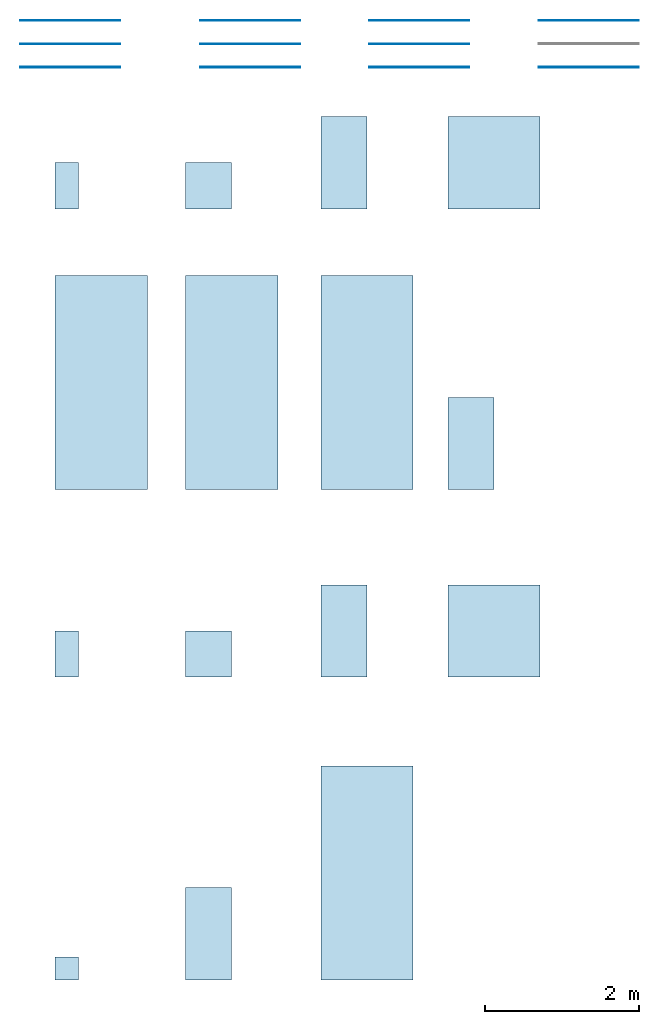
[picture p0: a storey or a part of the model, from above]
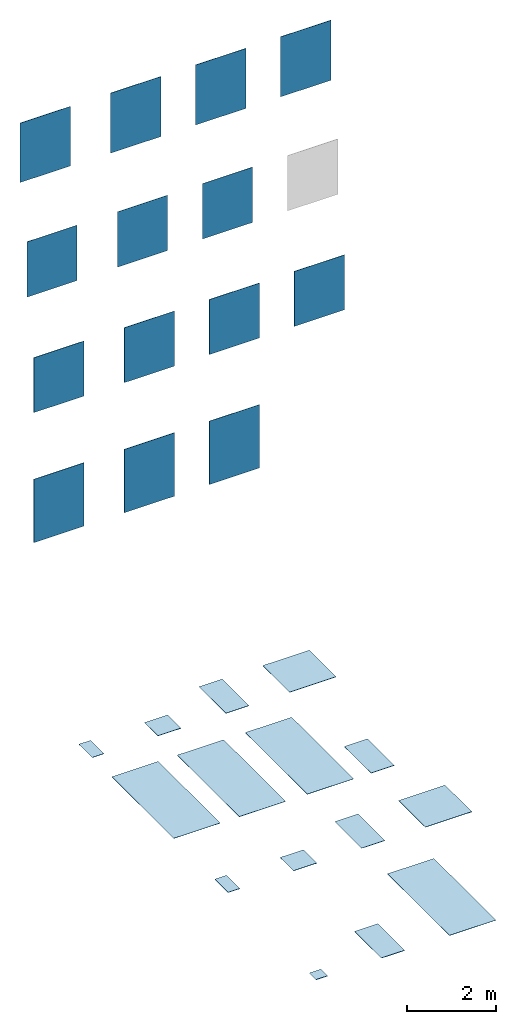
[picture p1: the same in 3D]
Properties of the parts of a building model (IFC2X3)

# File
Description: ViewDefinition [CoordinationView_V2.0], RevitIdentifiers [VersionGUID: 7166f2e5-5466-4735-995f-0db0073978aa, NumberOfSaves: 317], CoordinateReference [CoordinateBase: Shared Coordinates, ProjectSite: Internal]
File name: Project Number
Time: 2024-01-23T16:55:25+01:00
Written by: ODA SDAI 24.3
Made in: Autodesk Revit 24.1.11.26 (ENU) - IFC 24.1.11.26

# IfcProject, Project Number
LongName: Refin-Blended; Phase: Project Status

# IfcSite, Default
RefLatitude: 51, 30, 0, 549316; RefLongitude: 0, -7, -34, -450321; RefElevation: 0 mm

# IfcBuilding
Pset_BuildingCommon - NumberOfStoreys: 1

# IfcBuildingStorey: Level:Circle Head - Project Datum (2)
Pset_AirSideSystemInformation - sets with these values: 2
Name | LongName = Name | Elevation (mm)
Level 0 | Level 0 | 0
Level 1 | Level 1 | 4000

# IfcSlab: Floor:Floor_Tiles_Refin-Prestigio-Calacatta-Oro-120x278 RA40, Floor:Floor_Tiles_Refin-Prestigio-Calacatta-Oro-120x278 RA40:358765
In: Level 0
Type - PredefinedType: FLOOR; Material: Prestigio-Calacatta-Oro-120x278 RA40 6 mm, <Unnamed> 1 mm
Type - Pset_ConcreteElementGeneral - FireRating: INERT
Type - Pset_ElementShading - Color: WHITE
Type - Pset_FireRatingProperties - SurfaceSpreadOfFlame: INERT
Type - Pset_ManufacturerOccurrence - BarCode: N/A; SerialNumber: N/A
Type - Pset_ManufacturerTypeInformation - ArticleNumber: RA40; ModelReference: RA40; ModelLabel: CALACATTA ORO R 120X278; Manufacturer: info@refin.it; ProductionYear: N/A
Type - Pset_PrecastConcreteElementGeneral - SerialNumber: N/A
Type - Pset_ProductRequirements - Name: Prestigio_Calacatta_Oro_120X278 R; Category: Pr_35_93_96_19:Ceramic tiles
Type - Pset_QuantityTakeOff - Reference: N/A
Type - Pset_ReinforcementBarPitchOfSlab - Description: PORCELAIN STONEWARE TILE; Reference: N/A
Type - Pset_SlabCommon - Reference: N/A; IsExternal: no; AcousticRating: N/A; FireRating: INERT; SurfaceSpreadOfFlame: INERT
Type - Pset_Warranty - WarrantyContent: N/A; Exclusions: N/A
Pset_QuantityTakeOff - sets with these values: 2
Pset_SlabCommon - LoadBearing: no; PitchAngle: 0 deg

# IfcSlab: Floor:Floor_Tiles_Refin-Prestigio-Calacatta-Oro-Lucido-120x120 OY47, Floor:Floor_Tiles_Refin-Prestigio-Calacatta-Oro-Lucido-120x120 OY47:346245
In: Level 0
Type - PredefinedType: FLOOR; Material: Prestigio-Calacatta-Oro-Lucido-120x120 OY47 9 mm, <Unnamed> 1 mm
Type - Pset_ConcreteElementGeneral - FireRating: INERT
Type - Pset_ElementShading - Color: WHITE
Type - Pset_FireRatingProperties - SurfaceSpreadOfFlame: INERT
Type - Pset_ManufacturerOccurrence - BarCode: N/A; SerialNumber: N/A
Type - Pset_ManufacturerTypeInformation - ArticleNumber: OY47; ModelReference: OY47; ModelLabel: CALACATTA ORO LUCIDO R 120X120; Manufacturer: info@refin.it; ProductionYear: N/A
Type - Pset_PrecastConcreteElementGeneral - SerialNumber: N/A
Type - Pset_ProductRequirements - Name: Prestigio_Calacatta_Oro_Lucido_120X120 R; Category: Pr_35_93_96_19:Ceramic tiles
Type - Pset_QuantityTakeOff - Reference: N/A
Type - Pset_ReinforcementBarPitchOfSlab - Description: PORCELAIN STONEWARE TILE; Reference: N/A
Type - Pset_SlabCommon - Reference: N/A; IsExternal: no; AcousticRating: N/A; FireRating: INERT; SurfaceSpreadOfFlame: INERT
Type - Pset_Warranty - WarrantyContent: N/A; Exclusions: N/A
Pset_QuantityTakeOff - sets with these values: 2
Pset_SlabCommon - LoadBearing: no; PitchAngle: 0 deg

# IfcSlab: Floor:Floor_Tiles_Refin-Prestigio-Calacatta-Oro-Lucido-120x278 RA36, Floor:Floor_Tiles_Refin-Prestigio-Calacatta-Oro-Lucido-120x278 RA36:356121
In: Level 0
Type - PredefinedType: FLOOR; Material: Prestigio-Calacatta-Oro-Lucido-120x278 RA36 6 mm, <Unnamed> 1 mm
Type - Pset_ConcreteElementGeneral - FireRating: INERT
Type - Pset_ElementShading - Color: WHITE
Type - Pset_FireRatingProperties - SurfaceSpreadOfFlame: INERT
Type - Pset_ManufacturerOccurrence - BarCode: N/A; SerialNumber: N/A
Type - Pset_ManufacturerTypeInformation - ArticleNumber: RA36; ModelReference: RA36; ModelLabel: CALACATTA ORO LUCIDO R 120X278; Manufacturer: info@refin.it; ProductionYear: N/A
Type - Pset_PrecastConcreteElementGeneral - SerialNumber: N/A
Type - Pset_ProductRequirements - Name: Prestigio_Calacatta_Oro_Lucido_120X278 R; Category: Pr_35_93_96_19:Ceramic tiles
Type - Pset_QuantityTakeOff - Reference: N/A
Type - Pset_ReinforcementBarPitchOfSlab - Description: PORCELAIN STONEWARE TILE; Reference: N/A
Type - Pset_SlabCommon - Reference: N/A; IsExternal: no; AcousticRating: N/A; FireRating: INERT; SurfaceSpreadOfFlame: INERT
Type - Pset_Warranty - WarrantyContent: N/A; Exclusions: N/A
Pset_QuantityTakeOff - sets with these values: 2
Pset_SlabCommon - LoadBearing: no; PitchAngle: 0 deg

# IfcSlab: Floor:Floor_Tiles_Refin-Prestigio-Calacatta-Oro-Lucido-30x60 RC57, Floor:Floor_Tiles_Refin-Prestigio-Calacatta-Oro-Lucido-30x60 RC57:304668
In: Level 0
Type - PredefinedType: FLOOR; Material: Prestigio-Calacatta-Oro-Lucido-30x60 RC57 9 mm, <Unnamed> 1 mm
Type - Pset_ConcreteElementGeneral - FireRating: INERT
Type - Pset_ElementShading - Color: WHITE
Type - Pset_FireRatingProperties - SurfaceSpreadOfFlame: INERT
Type - Pset_ManufacturerOccurrence - BarCode: N/A; SerialNumber: N/A
Type - Pset_ManufacturerTypeInformation - ArticleNumber: RC57; ModelReference: RC57; ModelLabel: CALACATTA ORO LUCIDO R 30X60; Manufacturer: info@refin.it; ProductionYear: N/A
Type - Pset_PrecastConcreteElementGeneral - SerialNumber: N/A
Type - Pset_ProductRequirements - Name: Prestigio_Calacatta_Oro_Lucido_30X60 R; Category: Pr_35_93_96_19:Ceramic tiles
Type - Pset_QuantityTakeOff - Reference: N/A
Type - Pset_ReinforcementBarPitchOfSlab - Description: PORCELAIN STONEWARE TILE; Reference: N/A
Type - Pset_SlabCommon - Reference: N/A; IsExternal: no; AcousticRating: N/A; FireRating: INERT; SurfaceSpreadOfFlame: INERT
Type - Pset_Warranty - WarrantyContent: N/A; Exclusions: N/A
Pset_QuantityTakeOff - sets with these values: 2
Pset_SlabCommon - LoadBearing: no; PitchAngle: 0 deg

# IfcSlab: Floor:Floor_Tiles_Refin-Prestigio-Calacatta-Oro-Lucido-60x120 RC42, Floor:Floor_Tiles_Refin-Prestigio-Calacatta-Oro-Lucido-60x120 RC42:285295
In: Level 0
Type - PredefinedType: FLOOR; Material: Prestigio-Calacatta-Oro-Lucido-60x120 RC42 9 mm, <Unnamed> 1 mm
Type - Pset_ConcreteElementGeneral - FireRating: INERT
Type - Pset_ElementShading - Color: WHITE
Type - Pset_FireRatingProperties - SurfaceSpreadOfFlame: INERT
Type - Pset_ManufacturerOccurrence - BarCode: N/A; SerialNumber: N/A
Type - Pset_ManufacturerTypeInformation - ArticleNumber: RC42; ModelReference: RC42; ModelLabel: CALACATTA ORO LUCIDO R 60X120; Manufacturer: info@refin.it; ProductionYear: N/A
Type - Pset_PrecastConcreteElementGeneral - SerialNumber: N/A
Type - Pset_ProductRequirements - Name: Prestigio_Calacatta_Oro_Lucido_60X120 R; Category: Pr_35_93_96_19:Ceramic tiles
Type - Pset_QuantityTakeOff - Reference: N/A
Type - Pset_ReinforcementBarPitchOfSlab - Description: PORCELAIN STONEWARE TILE; Reference: N/A
Type - Pset_SlabCommon - Reference: N/A; IsExternal: no; AcousticRating: N/A; FireRating: INERT; SurfaceSpreadOfFlame: INERT
Type - Pset_Warranty - WarrantyContent: N/A; Exclusions: N/A
Pset_QuantityTakeOff - sets with these values: 2
Pset_SlabCommon - LoadBearing: no; PitchAngle: 0 deg

# IfcSlab: Floor:Floor_Tiles_Refin-Prestigio-Calacatta-Oro-Lucido-60x60 RA49, Floor:Floor_Tiles_Refin-Prestigio-Calacatta-Oro-Lucido-60x60 RA49:324498
In: Level 0
Type - PredefinedType: FLOOR; Material: Prestigio-Calacatta-Oro-Lucido-60x60 RA49 9 mm, <Unnamed> 1 mm
Type - Pset_ConcreteElementGeneral - FireRating: INERT
Type - Pset_ElementShading - Color: WHITE
Type - Pset_FireRatingProperties - SurfaceSpreadOfFlame: INERT
Type - Pset_ManufacturerOccurrence - BarCode: N/A; SerialNumber: N/A
Type - Pset_ManufacturerTypeInformation - ArticleNumber: RA49; ModelReference: RA49; ModelLabel: CALACATTA ORO LUCIDO R 60X60; Manufacturer: info@refin.it; ProductionYear: N/A
Type - Pset_PrecastConcreteElementGeneral - SerialNumber: N/A
Type - Pset_ProductRequirements - Name: Prestigio_Calacatta_Oro_Lucido_60X60 R; Category: Pr_35_93_96_19:Ceramic tiles
Type - Pset_QuantityTakeOff - Reference: N/A
Type - Pset_ReinforcementBarPitchOfSlab - Description: PORCELAIN STONEWARE TILE; Reference: N/A
Type - Pset_SlabCommon - Reference: N/A; IsExternal: no; AcousticRating: N/A; FireRating: INERT; SurfaceSpreadOfFlame: INERT
Type - Pset_Warranty - WarrantyContent: N/A; Exclusions: N/A
Pset_QuantityTakeOff - sets with these values: 2
Pset_SlabCommon - LoadBearing: no; PitchAngle: 0 deg

# IfcSlab: Floor:Floor_Tiles_Refin-Prestigio-Calacatta-Oro-Lucido-Craquele-120x278 RB39, Floor:Floor_Tiles_Refin-Prestigio-Calacatta-Oro-Lucido-Craquele-120x278 RB39:356309
In: Level 0
Type - PredefinedType: FLOOR; Material: Prestigio-Calacatta-Oro-Lucido-Craquele-120x278 RB39 6 mm, <Unnamed> 1 mm
Type - Pset_ConcreteElementGeneral - FireRating: INERT
Type - Pset_ElementShading - Color: WHITE
Type - Pset_FireRatingProperties - SurfaceSpreadOfFlame: INERT
Type - Pset_ManufacturerOccurrence - BarCode: N/A; SerialNumber: N/A
Type - Pset_ManufacturerTypeInformation - ArticleNumber: RB39; ModelReference: RB39; ModelLabel: CALACATTA ORO LUCIDO CRAQUELE R 120X278; Manufacturer: info@refin.it; ProductionYear: N/A
Type - Pset_PrecastConcreteElementGeneral - SerialNumber: N/A
Type - Pset_ProductRequirements - Name: Prestigio_Calacatta_Oro_Lucido_Craquele_120X278 R; Category: Pr_35_93_96_19:Ceramic tiles
Type - Pset_QuantityTakeOff - Reference: N/A
Type - Pset_ReinforcementBarPitchOfSlab - Description: PORCELAIN STONEWARE TILE; Reference: N/A
Type - Pset_SlabCommon - Reference: N/A; IsExternal: no; AcousticRating: N/A; FireRating: INERT; SurfaceSpreadOfFlame: INERT
Type - Pset_Warranty - WarrantyContent: N/A; Exclusions: N/A
Pset_QuantityTakeOff - sets with these values: 2
Pset_SlabCommon - LoadBearing: no; PitchAngle: 0 deg

# IfcSlab: Floor:Floor_Tiles_Refin-Prestigio-Calacatta-Oro-Lucido-Mesh-120x278 RB41, Floor:Floor_Tiles_Refin-Prestigio-Calacatta-Oro-Lucido-Mesh-120x278 RB41:356759
In: Level 0
Type - PredefinedType: FLOOR; Material: Prestigio-Calacatta-Oro-Lucido-Mesh-120x278 RB41 6 mm, <Unnamed> 1 mm
Type - Pset_ConcreteElementGeneral - FireRating: INERT
Type - Pset_ElementShading - Color: WHITE
Type - Pset_FireRatingProperties - SurfaceSpreadOfFlame: INERT
Type - Pset_ManufacturerOccurrence - BarCode: N/A; SerialNumber: N/A
Type - Pset_ManufacturerTypeInformation - ArticleNumber: RB41; ModelReference: RB41; ModelLabel: CALACATTA ORO LUCIDO MESH R 120X278; Manufacturer: info@refin.it; ProductionYear: N/A
Type - Pset_PrecastConcreteElementGeneral - SerialNumber: N/A
Type - Pset_ProductRequirements - Name: Prestigio_Calacatta_Oro_Lucido_Mesh_120X278 R; Category: Pr_35_93_96_19:Ceramic tiles
Type - Pset_QuantityTakeOff - Reference: N/A
Type - Pset_ReinforcementBarPitchOfSlab - Description: PORCELAIN STONEWARE TILE; Reference: N/A
Type - Pset_SlabCommon - Reference: N/A; IsExternal: no; AcousticRating: N/A; FireRating: INERT; SurfaceSpreadOfFlame: INERT
Type - Pset_Warranty - WarrantyContent: N/A; Exclusions: N/A
Pset_QuantityTakeOff - sets with these values: 2
Pset_SlabCommon - LoadBearing: no; PitchAngle: 0 deg

# IfcSlab: Floor:Floor_Tiles_Refin-Prestigio-Calacatta-Oro-Matt-60x120 RC52, Floor:Floor_Tiles_Refin-Prestigio-Calacatta-Oro-Matt-60x120 RC52:356962
In: Level 0
Type - PredefinedType: FLOOR; Material: Prestigio-Calacatta-Oro-Matt-60x120 RC52 9 mm, <Unnamed> 1 mm
Type - Pset_ConcreteElementGeneral - FireRating: INERT
Type - Pset_ElementShading - Color: WHITE
Type - Pset_FireRatingProperties - SurfaceSpreadOfFlame: INERT
Type - Pset_ManufacturerOccurrence - BarCode: N/A; SerialNumber: N/A
Type - Pset_ManufacturerTypeInformation - ArticleNumber: RC52; ModelReference: RC52; ModelLabel: CALACATTA ORO MATT R 60X120; Manufacturer: info@refin.it; ProductionYear: N/A
Type - Pset_PrecastConcreteElementGeneral - SerialNumber: N/A
Type - Pset_ProductRequirements - Name: Prestigio_Calacatta_Oro_Matt_60X120 R; Category: Pr_35_93_96_19:Ceramic tiles
Type - Pset_QuantityTakeOff - Reference: N/A
Type - Pset_ReinforcementBarPitchOfSlab - Description: PORCELAIN STONEWARE TILE; Reference: N/A
Type - Pset_SlabCommon - Reference: N/A; IsExternal: no; AcousticRating: N/A; FireRating: INERT; SurfaceSpreadOfFlame: INERT
Type - Pset_Warranty - WarrantyContent: N/A; Exclusions: N/A
Pset_QuantityTakeOff - sets with these values: 2
Pset_SlabCommon - LoadBearing: no; PitchAngle: 0 deg

# IfcSlab: Floor:Floor_Tiles_Refin-Prestigio-Calacatta-Oro-Mosaico-30x30 RB56, Floor:Floor_Tiles_Refin-Prestigio-Calacatta-Oro-Mosaico-30x30 RB56:358331
In: Level 0
Type - PredefinedType: FLOOR; Material: Prestigio-Calacatta-Oro-Mosaico-30x30 RB56 9 mm, <Unnamed> 1 mm
Type - Pset_ConcreteElementGeneral - FireRating: INERT
Type - Pset_ElementShading - Color: WHITE
Type - Pset_FireRatingProperties - SurfaceSpreadOfFlame: INERT
Type - Pset_ManufacturerOccurrence - BarCode: N/A; SerialNumber: N/A
Type - Pset_ManufacturerTypeInformation - ArticleNumber: RB56; ModelReference: RB56; ModelLabel: CALACATTA ORO MOSAICO R 30X30; Manufacturer: info@refin.it; ProductionYear: N/A
Type - Pset_PrecastConcreteElementGeneral - SerialNumber: N/A
Type - Pset_ProductRequirements - Name: Prestigio_Calacatta_Oro_Mosaico_30X30 R; Category: Pr_35_93_96_19:Ceramic tiles
Type - Pset_QuantityTakeOff - Reference: N/A
Type - Pset_ReinforcementBarPitchOfSlab - Description: PORCELAIN STONEWARE TILE; Reference: N/A
Type - Pset_SlabCommon - Reference: N/A; IsExternal: no; AcousticRating: N/A; FireRating: INERT; SurfaceSpreadOfFlame: INERT
Type - Pset_Warranty - WarrantyContent: N/A; Exclusions: N/A
Pset_QuantityTakeOff - sets with these values: 2
Pset_SlabCommon - LoadBearing: no; PitchAngle: 0 deg

# IfcSlab: Floor:Floor_Tiles_Refin-Prestigio-Calacatta-Oro-Onde-60x120 RB12, Floor:Floor_Tiles_Refin-Prestigio-Calacatta-Oro-Onde-60x120 RB12:353888
In: Level 0
Type - PredefinedType: FLOOR; Material: Prestigio-Calacatta-Oro-Onde-60x120 RB12 9 mm, <Unnamed> 1 mm
Type - Pset_ConcreteElementGeneral - FireRating: INERT
Type - Pset_ElementShading - Color: WHITE
Type - Pset_FireRatingProperties - SurfaceSpreadOfFlame: INERT
Type - Pset_ManufacturerOccurrence - BarCode: N/A; SerialNumber: N/A
Type - Pset_ManufacturerTypeInformation - ArticleNumber: RB12; ModelReference: RB12; ModelLabel: CALACATTA ORO ONDE R 60X120; Manufacturer: info@refin.it; ProductionYear: N/A
Type - Pset_PrecastConcreteElementGeneral - SerialNumber: N/A
Type - Pset_ProductRequirements - Name: Prestigio_Calacatta_Oro_Onde_60X120 R; Category: Pr_35_93_96_19:Ceramic tiles
Type - Pset_QuantityTakeOff - Reference: N/A
Type - Pset_ReinforcementBarPitchOfSlab - Description: PORCELAIN STONEWARE TILE; Reference: N/A
Type - Pset_SlabCommon - Reference: N/A; IsExternal: no; AcousticRating: N/A; FireRating: INERT; SurfaceSpreadOfFlame: INERT
Type - Pset_Warranty - WarrantyContent: N/A; Exclusions: N/A
Pset_QuantityTakeOff - sets with these values: 2
Pset_SlabCommon - LoadBearing: no; PitchAngle: 0 deg

# IfcSlab: Floor:Floor_Tiles_Refin-Prestigio-Calacatta-Oro-Soft-120x120 OY58, Floor:Floor_Tiles_Refin-Prestigio-Calacatta-Oro-Soft-120x120 OY58:357396
In: Level 0
Type - PredefinedType: FLOOR; Material: Prestigio-Calacatta-Oro-Soft-120x120 OY58 9 mm, <Unnamed> 1 mm
Type - Pset_ConcreteElementGeneral - FireRating: INERT
Type - Pset_ElementShading - Color: WHITE
Type - Pset_FireRatingProperties - SurfaceSpreadOfFlame: INERT
Type - Pset_ManufacturerOccurrence - BarCode: N/A; SerialNumber: N/A
Type - Pset_ManufacturerTypeInformation - ArticleNumber: OY58; ModelReference: OY58; ModelLabel: CALACATTA ORO SOFT R 120X120; Manufacturer: info@refin.it; ProductionYear: N/A
Type - Pset_PrecastConcreteElementGeneral - SerialNumber: N/A
Type - Pset_ProductRequirements - Name: Prestigio_Calacatta_Oro_Soft_120X120 R; Category: Pr_35_93_96_19:Ceramic tiles
Type - Pset_QuantityTakeOff - Reference: N/A
Type - Pset_ReinforcementBarPitchOfSlab - Description: PORCELAIN STONEWARE TILE; Reference: N/A
Type - Pset_SlabCommon - Reference: N/A; IsExternal: no; AcousticRating: N/A; FireRating: INERT; SurfaceSpreadOfFlame: INERT
Type - Pset_Warranty - WarrantyContent: N/A; Exclusions: N/A
Pset_QuantityTakeOff - sets with these values: 2
Pset_SlabCommon - LoadBearing: no; PitchAngle: 0 deg

# IfcSlab: Floor:Floor_Tiles_Refin-Prestigio-Calacatta-Oro-Soft-30x60 RC62, Floor:Floor_Tiles_Refin-Prestigio-Calacatta-Oro-Soft-30x60 RC62:357145
In: Level 0
Type - PredefinedType: FLOOR; Material: Prestigio-Calacatta-Oro-Soft-30x60 RC62 9 mm, <Unnamed> 1 mm
Type - Pset_ConcreteElementGeneral - FireRating: INERT
Type - Pset_ElementShading - Color: WHITE
Type - Pset_FireRatingProperties - SurfaceSpreadOfFlame: INERT
Type - Pset_ManufacturerOccurrence - BarCode: N/A; SerialNumber: N/A
Type - Pset_ManufacturerTypeInformation - ArticleNumber: RC62; ModelReference: RC62; ModelLabel: CALACATTA ORO SOFT R 30X60; Manufacturer: info@refin.it; ProductionYear: N/A
Type - Pset_PrecastConcreteElementGeneral - SerialNumber: N/A
Type - Pset_ProductRequirements - Name: Prestigio_Calacatta_Oro_Soft_30X60 R; Category: Pr_35_93_96_19:Ceramic tiles
Type - Pset_QuantityTakeOff - Reference: N/A
Type - Pset_ReinforcementBarPitchOfSlab - Description: PORCELAIN STONEWARE TILE; Reference: N/A
Type - Pset_SlabCommon - Reference: N/A; IsExternal: no; AcousticRating: N/A; FireRating: INERT; SurfaceSpreadOfFlame: INERT
Type - Pset_Warranty - WarrantyContent: N/A; Exclusions: N/A
Pset_QuantityTakeOff - sets with these values: 2
Pset_SlabCommon - LoadBearing: no; PitchAngle: 0 deg

# IfcSlab: Floor:Floor_Tiles_Refin-Prestigio-Calacatta-Oro-Soft-60x120 RC47, Floor:Floor_Tiles_Refin-Prestigio-Calacatta-Oro-Soft-60x120 RC47:357388
In: Level 0
Type - PredefinedType: FLOOR; Material: Prestigio-Calacatta-Oro-Soft-60x120 RC47 6 mm, <Unnamed> 1 mm
Type - Pset_ConcreteElementGeneral - FireRating: INERT
Type - Pset_ElementShading - Color: WHITE
Type - Pset_FireRatingProperties - SurfaceSpreadOfFlame: INERT
Type - Pset_ManufacturerOccurrence - BarCode: N/A; SerialNumber: N/A
Type - Pset_ManufacturerTypeInformation - ArticleNumber: RC47; ModelReference: RC47; ModelLabel: CALACATTA ORO SOFT R 60X120; Manufacturer: info@refin.it; ProductionYear: N/A
Type - Pset_PrecastConcreteElementGeneral - SerialNumber: N/A
Type - Pset_ProductRequirements - Name: Prestigio_Calacatta_Oro_Soft_60X120 R; Category: Pr_35_93_96_19:Ceramic tiles
Type - Pset_QuantityTakeOff - Reference: N/A
Type - Pset_ReinforcementBarPitchOfSlab - Description: PORCELAIN STONEWARE TILE; Reference: N/A
Type - Pset_SlabCommon - Reference: N/A; IsExternal: no; AcousticRating: N/A; FireRating: INERT; SurfaceSpreadOfFlame: INERT
Type - Pset_Warranty - WarrantyContent: N/A; Exclusions: N/A
Pset_QuantityTakeOff - sets with these values: 2
Pset_SlabCommon - LoadBearing: no; PitchAngle: 0 deg

# IfcSlab: Floor:Floor_Tiles_Refin-Prestigio-Calacatta-Oro-Soft-60x60 RB85, Floor:Floor_Tiles_Refin-Prestigio-Calacatta-Oro-Soft-60x60 RB85:357443
In: Level 0
Type - PredefinedType: FLOOR; Material: Prestigio-Calacatta-Oro-Lucido-60x60 RA49 9 mm, <Unnamed> 1 mm
Type - Pset_ConcreteElementGeneral - FireRating: INERT
Type - Pset_ElementShading - Color: WHITE
Type - Pset_FireRatingProperties - SurfaceSpreadOfFlame: INERT
Type - Pset_ManufacturerOccurrence - BarCode: N/A; SerialNumber: N/A
Type - Pset_ManufacturerTypeInformation - ArticleNumber: RB85; ModelReference: RB85; ModelLabel: CALACATTA ORO SOFT R 60X60; Manufacturer: info@refin.it; ProductionYear: N/A
Type - Pset_PrecastConcreteElementGeneral - SerialNumber: N/A
Type - Pset_ProductRequirements - Name: Prestigio_Calacatta_Oro_Soft_60X60 R; Category: Pr_35_93_96_19:Ceramic tiles
Type - Pset_QuantityTakeOff - Reference: N/A
Type - Pset_ReinforcementBarPitchOfSlab - Description: PORCELAIN STONEWARE TILE; Reference: N/A
Type - Pset_SlabCommon - Reference: N/A; IsExternal: no; AcousticRating: N/A; FireRating: INERT; SurfaceSpreadOfFlame: INERT
Type - Pset_Warranty - WarrantyContent: N/A; Exclusions: N/A
Pset_QuantityTakeOff - sets with these values: 2
Pset_SlabCommon - LoadBearing: no; PitchAngle: 0 deg

# IfcWallStandardCase: Basic Wall:Wall_Tiles_Refin-Prestigio-Calacatta-Oro-Lucido-120x120 OY47, Basic Wall:Wall_Tiles_Refin-Prestigio-Calacatta-Oro-Lucido-120x120 OY47:346671
In: Level 0
Type - PredefinedType: STANDARD; Material: <Unnamed> 1 mm, Prestigio-Calacatta-Oro-Lucido-120x120 OY47 9 mm
Type - Pset_ElementShading - Color: WHITE
Type - Pset_FireRatingProperties - SurfaceSpreadOfFlame: INERT
Type - Pset_ManufacturerOccurrence - BarCode: N/A; SerialNumber: N/A
Type - Pset_ManufacturerTypeInformation - ArticleNumber: OY47; ModelReference: OY47; ModelLabel: CALACATTA ORO LUCIDO R 120X120; Manufacturer: info@refin.it; ProductionYear: N/A
Type - Pset_PrecastConcreteElementGeneral - SerialNumber: N/A
Type - Pset_ProductRequirements - Name: Prestigio_Calacatta_Oro_Lucido_120X120 R; Category: Pr_35_93_96_19:Ceramic tiles
Type - Pset_QuantityTakeOff - Reference: N/A
Type - Pset_ReinforcementBarPitchOfWall - Description: PORCELAIN STONEWARE TILE; Reference: N/A
Type - Pset_WallCommon - Reference: N/A; IsExternal: no; AcousticRating: N/A; SurfaceSpreadOfFlame: INERT
Type - Pset_Warranty - WarrantyContent: N/A; Exclusions: N/A
Pset_QuantityTakeOff - sets with these values: 2
Pset_WallCommon - LoadBearing: no; ExtendToStructure: no

# IfcWallStandardCase: Basic Wall:Wall_Tiles_Refin-Prestigio-Calacatta-Oro-Lucido-120x278 RA36, Basic Wall:Wall_Tiles_Refin-Prestigio-Calacatta-Oro-Lucido-120x278 RA36:335038
In: Level 0
Type - PredefinedType: STANDARD; Material: <Unnamed> 1 mm, Prestigio-Calacatta-Oro-Lucido-120x278 RA36 6 mm
Type - Pset_ElementShading - Color: WHITE
Type - Pset_FireRatingProperties - SurfaceSpreadOfFlame: INERT
Type - Pset_ManufacturerOccurrence - BarCode: N/A; SerialNumber: N/A
Type - Pset_ManufacturerTypeInformation - ArticleNumber: RB39; ModelReference: RB39; ModelLabel: CALACATTA ORO LUCIDO R 120X278; Manufacturer: info@refin.it; ProductionYear: N/A
Type - Pset_PrecastConcreteElementGeneral - SerialNumber: N/A
Type - Pset_ProductRequirements - Name: Prestigio_Calacatta_Oro_Lucido_120X278 R; Category: Pr_35_93_96_19:Ceramic tiles
Type - Pset_QuantityTakeOff - Reference: N/A
Type - Pset_ReinforcementBarPitchOfWall - Description: PORCELAIN STONEWARE TILE; Reference: N/A
Type - Pset_WallCommon - Reference: N/A; IsExternal: no; AcousticRating: N/A; SurfaceSpreadOfFlame: INERT
Type - Pset_Warranty - WarrantyContent: N/A; Exclusions: N/A
Pset_QuantityTakeOff - sets with these values: 2
Pset_WallCommon - LoadBearing: no; ExtendToStructure: no

# IfcWallStandardCase: Basic Wall:Wall_Tiles_Refin-Prestigio-Calacatta-Oro-Lucido-30x60 RC57, Basic Wall:Wall_Tiles_Refin-Prestigio-Calacatta-Oro-Lucido-30x60 RC57:334895
In: Level 0
Type - PredefinedType: STANDARD; Material: <Unnamed> 1 mm, Prestigio-Calacatta-Oro-Lucido-30x60 RC57 9 mm
Type - Pset_ElementShading - Color: WHITE
Type - Pset_FireRatingProperties - SurfaceSpreadOfFlame: INERT
Type - Pset_ManufacturerOccurrence - BarCode: N/A; SerialNumber: N/A
Type - Pset_ManufacturerTypeInformation - ArticleNumber: RC57; ModelReference: RC57; ModelLabel: CALACATTA ORO LUCIDO R 30X60; Manufacturer: info@refin.it; ProductionYear: N/A
Type - Pset_PrecastConcreteElementGeneral - SerialNumber: N/A
Type - Pset_ProductRequirements - Name: Prestigio_Calacatta_Oro_Lucido_30X60 R; Category: Pr_35_93_96_19:Ceramic tiles
Type - Pset_QuantityTakeOff - Reference: N/A
Type - Pset_ReinforcementBarPitchOfWall - Description: PORCELAIN STONEWARE TILE; Reference: N/A
Type - Pset_WallCommon - Reference: N/A; IsExternal: no; AcousticRating: N/A; SurfaceSpreadOfFlame: INERT
Type - Pset_Warranty - WarrantyContent: N/A; Exclusions: N/A
Pset_QuantityTakeOff - sets with these values: 2
Pset_WallCommon - LoadBearing: no; ExtendToStructure: no

# IfcWallStandardCase: Basic Wall:Wall_Tiles_Refin-Prestigio-Calacatta-Oro-Lucido-60x120 RC42, Basic Wall:Wall_Tiles_Refin-Prestigio-Calacatta-Oro-Lucido-60x120 RC42:334553
In: Level 0
Type - PredefinedType: STANDARD; Material: <Unnamed> 1 mm, Prestigio-Calacatta-Oro-Lucido-60x120 RC42 9 mm
Type - Pset_ElementShading - Color: WHITE
Type - Pset_FireRatingProperties - SurfaceSpreadOfFlame: INERT
Type - Pset_ManufacturerOccurrence - BarCode: N/A; SerialNumber: N/A
Type - Pset_ManufacturerTypeInformation - ArticleNumber: RC42; ModelReference: RC42; ModelLabel: CALACATTA ORO LUCIDO R 60X120; Manufacturer: info@refin.it; ProductionYear: N/A
Type - Pset_PrecastConcreteElementGeneral - SerialNumber: N/A
Type - Pset_ProductRequirements - Name: Prestigio_Calacatta_Oro_Lucido_60X120 R; Category: Pr_35_93_96_19:Ceramic tiles
Type - Pset_QuantityTakeOff - Reference: N/A
Type - Pset_ReinforcementBarPitchOfWall - Description: PORCELAIN STONEWARE TILE; Reference: N/A
Type - Pset_WallCommon - Reference: N/A; IsExternal: no; AcousticRating: N/A; SurfaceSpreadOfFlame: INERT
Type - Pset_Warranty - WarrantyContent: N/A; Exclusions: N/A
Pset_QuantityTakeOff - sets with these values: 2
Pset_WallCommon - LoadBearing: no; ExtendToStructure: no

# IfcWallStandardCase: Basic Wall:Wall_Tiles_Refin-Prestigio-Calacatta-Oro-Lucido-60x60 RA49, Basic Wall:Wall_Tiles_Refin-Prestigio-Calacatta-Oro-Lucido-60x60 RA49:333696
In: Level 0
Type - PredefinedType: STANDARD; Material: <Unnamed> 1 mm, Prestigio-Calacatta-Oro-Lucido-60x60 RA49 9 mm
Type - Pset_ElementShading - Color: WHITE
Type - Pset_FireRatingProperties - SurfaceSpreadOfFlame: INERT
Type - Pset_ManufacturerOccurrence - BarCode: N/A; SerialNumber: N/A
Type - Pset_ManufacturerTypeInformation - ArticleNumber: RA49; ModelReference: RA49; ModelLabel: CALACATTA ORO LUCIDO R 60X60; Manufacturer: info@refin.it; ProductionYear: N/A
Type - Pset_PrecastConcreteElementGeneral - SerialNumber: N/A
Type - Pset_ProductRequirements - Name: Prestigio_Calacatta_Oro_Lucido_60X60 R; Category: Pr_35_93_96_19:Ceramic tiles
Type - Pset_QuantityTakeOff - Reference: N/A
Type - Pset_ReinforcementBarPitchOfWall - Description: PORCELAIN STONEWARE TILE; Reference: N/A
Type - Pset_WallCommon - Reference: N/A; IsExternal: no; AcousticRating: N/A; SurfaceSpreadOfFlame: INERT
Type - Pset_Warranty - WarrantyContent: N/A; Exclusions: N/A
Pset_QuantityTakeOff - sets with these values: 2
Pset_WallCommon - LoadBearing: no; ExtendToStructure: no

# IfcWallStandardCase: Basic Wall:Wall_Tiles_Refin-Prestigio-Calacatta-Oro-Lucido-Craquele-120x278 RB39, Basic Wall:Wall_Tiles_Refin-Prestigio-Calacatta-Oro-Lucido-Craquele-120x278 RB39:335490
In: Level 0
Type - PredefinedType: STANDARD; Material: <Unnamed> 1 mm, Prestigio-Calacatta-Oro-Lucido-Craquele-120x278 RB39 6 mm
Type - Pset_ElementShading - Color: WHITE
Type - Pset_FireRatingProperties - SurfaceSpreadOfFlame: INERT
Type - Pset_ManufacturerOccurrence - BarCode: N/A; SerialNumber: N/A
Type - Pset_ManufacturerTypeInformation - ArticleNumber: RB39; ModelReference: RB39; ModelLabel: CALACATTA ORO LUCIDO CRAQUELE R 120X278; Manufacturer: info@refin.it; ProductionYear: N/A
Type - Pset_PrecastConcreteElementGeneral - SerialNumber: N/A
Type - Pset_ProductRequirements - Name: Prestigio_Calacatta_Oro_Lucido_Craquele_120X278 R; Category: Pr_35_93_96_19:Ceramic tiles
Type - Pset_QuantityTakeOff - Reference: N/A
Type - Pset_ReinforcementBarPitchOfWall - Description: PORCELAIN STONEWARE TILE; Reference: N/A
Type - Pset_WallCommon - Reference: N/A; IsExternal: no; AcousticRating: N/A; SurfaceSpreadOfFlame: INERT
Type - Pset_Warranty - WarrantyContent: N/A; Exclusions: N/A
Pset_QuantityTakeOff - sets with these values: 2
Pset_WallCommon - LoadBearing: no; ExtendToStructure: no

# IfcWallStandardCase: Basic Wall:Wall_Tiles_Refin-Prestigio-Calacatta-Oro-Lucido-Mesh-120x278 RB41, Basic Wall:Wall_Tiles_Refin-Prestigio-Calacatta-Oro-Lucido-Mesh-120x278 RB41:335882
In: Level 0
Type - PredefinedType: STANDARD; Material: <Unnamed> 1 mm, Prestigio-Calacatta-Oro-Lucido-Mesh-120x278 RB41 6 mm
Type - Pset_ElementShading - Color: WHITE
Type - Pset_FireRatingProperties - SurfaceSpreadOfFlame: INERT
Type - Pset_ManufacturerOccurrence - BarCode: N/A; SerialNumber: N/A
Type - Pset_ManufacturerTypeInformation - ArticleNumber: RB41; ModelReference: RB41; ModelLabel: CALACATTA ORO LUCIDO MESH R 120X278; Manufacturer: info@refin.it; ProductionYear: N/A
Type - Pset_PrecastConcreteElementGeneral - SerialNumber: N/A
Type - Pset_ProductRequirements - Name: Prestigio_Calacatta_Oro_Lucido_Mesh_120X278 R; Category: Pr_35_93_96_19:Ceramic tiles
Type - Pset_QuantityTakeOff - Reference: N/A
Type - Pset_ReinforcementBarPitchOfWall - Description: PORCELAIN STONEWARE TILE; Reference: N/A
Type - Pset_WallCommon - Reference: N/A; IsExternal: no; AcousticRating: N/A; SurfaceSpreadOfFlame: INERT
Type - Pset_Warranty - WarrantyContent: N/A; Exclusions: N/A
Pset_QuantityTakeOff - sets with these values: 2
Pset_WallCommon - LoadBearing: no; ExtendToStructure: no

# IfcWallStandardCase: Basic Wall:Wall_Tiles_Refin-Prestigio-Calacatta-Oro-Matt-60x120 RC52, Basic Wall:Wall_Tiles_Refin-Prestigio-Calacatta-Oro-Matt-60x120 RC52:346686
In: Level 0
Type - PredefinedType: STANDARD; Material: <Unnamed> 1 mm, Prestigio-Calacatta-Oro-Matt-60x120 RC52 9 mm
Type - Pset_ElementShading - Color: WHITE
Type - Pset_FireRatingProperties - SurfaceSpreadOfFlame: INERT
Type - Pset_ManufacturerOccurrence - BarCode: N/A; SerialNumber: N/A
Type - Pset_ManufacturerTypeInformation - ArticleNumber: RC52; ModelReference: RC52; ModelLabel: CALACATTA ORO MATT R 60X120; Manufacturer: info@refin.it; ProductionYear: N/A
Type - Pset_PrecastConcreteElementGeneral - SerialNumber: N/A
Type - Pset_ProductRequirements - Name: Prestigio_Calacatta_Oro_Matt_60X120 R; Category: Pr_35_93_96_19:Ceramic tiles
Type - Pset_QuantityTakeOff - Reference: N/A
Type - Pset_ReinforcementBarPitchOfWall - Description: PORCELAIN STONEWARE TILE; Reference: N/A
Type - Pset_WallCommon - Reference: N/A; IsExternal: no; AcousticRating: N/A; SurfaceSpreadOfFlame: INERT
Type - Pset_Warranty - WarrantyContent: N/A; Exclusions: N/A
Pset_QuantityTakeOff - sets with these values: 2
Pset_WallCommon - LoadBearing: no; ExtendToStructure: no

# IfcWallStandardCase: Basic Wall:Wall_Tiles_Refin-Prestigio-Calacatta-Oro-Mosaico-30x30 RB56, Basic Wall:Wall_Tiles_Refin-Prestigio-Calacatta-Oro-Mosaico-30x30 RB56:353999
In: Level 0
Type - PredefinedType: STANDARD; Material: <Unnamed> 1 mm, Prestigio-Calacatta-Oro-Mosaico-30x30 RB56 9 mm
Type - Pset_ElementShading - Color: WHITE
Type - Pset_FireRatingProperties - SurfaceSpreadOfFlame: INERT
Type - Pset_ManufacturerOccurrence - BarCode: N/A; SerialNumber: N/A
Type - Pset_ManufacturerTypeInformation - ArticleNumber: RB56; ModelReference: RB56; ModelLabel: CALACATTA ORO MOSAICO R 30X30; Manufacturer: info@refin.it; ProductionYear: N/A
Type - Pset_PrecastConcreteElementGeneral - SerialNumber: N/A
Type - Pset_ProductRequirements - Name: Prestigio_Calacatta_Oro_Mosaico_30X30 R; Category: Pr_35_93_96_19:Ceramic tiles
Type - Pset_QuantityTakeOff - Reference: N/A
Type - Pset_ReinforcementBarPitchOfWall - Description: PORCELAIN STONEWARE TILE; Reference: N/A
Type - Pset_WallCommon - Reference: N/A; IsExternal: no; AcousticRating: N/A; SurfaceSpreadOfFlame: INERT
Type - Pset_Warranty - WarrantyContent: N/A; Exclusions: N/A
Pset_QuantityTakeOff - sets with these values: 2
Pset_WallCommon - LoadBearing: no; ExtendToStructure: no

# IfcWallStandardCase: Basic Wall:Wall_Tiles_Refin-Prestigio-Calacatta-Oro-Onde-60x120 RB12, Basic Wall:Wall_Tiles_Refin-Prestigio-Calacatta-Oro-Onde-60x120 RB12:353930
In: Level 0
Type - PredefinedType: STANDARD; Material: <Unnamed> 1 mm, Prestigio-Calacatta-Oro-Onde-60x120 RB12 9 mm
Type - Pset_ElementShading - Color: WHITE
Type - Pset_FireRatingProperties - SurfaceSpreadOfFlame: INERT
Type - Pset_ManufacturerOccurrence - BarCode: N/A; SerialNumber: N/A
Type - Pset_ManufacturerTypeInformation - ArticleNumber: RB12; ModelReference: RB12; ModelLabel: CALACATTA ORO ONDE R 60X120; Manufacturer: info@refin.it; ProductionYear: N/A
Type - Pset_PrecastConcreteElementGeneral - SerialNumber: N/A
Type - Pset_ProductRequirements - Name: Prestigio_Calacatta_Oro_Onde_60X120 R; Category: Pr_35_93_96_19:Ceramic tiles
Type - Pset_QuantityTakeOff - Reference: N/A
Type - Pset_ReinforcementBarPitchOfWall - Description: PORCELAIN STONEWARE TILE; Reference: N/A
Type - Pset_WallCommon - Reference: N/A; IsExternal: no; AcousticRating: N/A; SurfaceSpreadOfFlame: INERT
Type - Pset_Warranty - WarrantyContent: N/A; Exclusions: N/A
Pset_QuantityTakeOff - sets with these values: 2
Pset_WallCommon - LoadBearing: no; ExtendToStructure: no

# IfcWallStandardCase: Basic Wall:Wall_Tiles_Refin-Prestigio-Calacatta-Oro-Soft-120x120 OY58, Basic Wall:Wall_Tiles_Refin-Prestigio-Calacatta-Oro-Soft-120x120 OY58:346688
In: Level 0
Type - PredefinedType: STANDARD; Material: <Unnamed> 1 mm, Prestigio-Calacatta-Oro-Soft-120x120 OY58 9 mm
Type - Pset_ElementShading - Color: WHITE
Type - Pset_FireRatingProperties - SurfaceSpreadOfFlame: INERT
Type - Pset_ManufacturerOccurrence - BarCode: N/A; SerialNumber: N/A
Type - Pset_ManufacturerTypeInformation - ArticleNumber: OY58; ModelReference: OY58; ModelLabel: CALACATTA ORO SOFT R 120X120; Manufacturer: info@refin.it; ProductionYear: N/A
Type - Pset_PrecastConcreteElementGeneral - SerialNumber: N/A
Type - Pset_ProductRequirements - Name: Prestigio_Calacatta_Oro_Soft_120X120 R; Category: Pr_35_93_96_19:Ceramic tiles
Type - Pset_QuantityTakeOff - Reference: N/A
Type - Pset_ReinforcementBarPitchOfWall - Description: PORCELAIN STONEWARE TILE; Reference: N/A
Type - Pset_WallCommon - Reference: N/A; IsExternal: no; AcousticRating: N/A; SurfaceSpreadOfFlame: INERT
Type - Pset_Warranty - WarrantyContent: N/A; Exclusions: N/A
Pset_QuantityTakeOff - sets with these values: 2
Pset_WallCommon - LoadBearing: no; ExtendToStructure: no

# IfcWallStandardCase: Basic Wall:Wall_Tiles_Refin-Prestigio-Calacatta-Oro-Soft-120x278 RA40, Basic Wall:Wall_Tiles_Refin-Prestigio-Calacatta-Oro-Soft-120x278 RA40:359236
In: Level 0
Type - PredefinedType: STANDARD; Material: <Unnamed> 1 mm, Prestigio-Calacatta-Oro-120x278 RA40 6 mm
Type - Pset_ElementShading - Color: WHITE
Type - Pset_FireRatingProperties - SurfaceSpreadOfFlame: INERT
Type - Pset_ManufacturerOccurrence - BarCode: N/A; SerialNumber: N/A
Type - Pset_ManufacturerTypeInformation - ArticleNumber: RA40; ModelReference: RA40; ModelLabel: CALACATTA ORO R 120X278; Manufacturer: info@refin.it; ProductionYear: N/A
Type - Pset_PrecastConcreteElementGeneral - SerialNumber: N/A
Type - Pset_ProductRequirements - Name: Prestigio_Calacatta_Oro_120X278 R; Category: Pr_35_93_96_19:Ceramic tiles
Type - Pset_QuantityTakeOff - Reference: N/A
Type - Pset_ReinforcementBarPitchOfWall - Description: PORCELAIN STONEWARE TILE; Reference: N/A
Type - Pset_WallCommon - Reference: N/A; IsExternal: no; AcousticRating: N/A; SurfaceSpreadOfFlame: INERT
Type - Pset_Warranty - WarrantyContent: N/A; Exclusions: N/A
Pset_QuantityTakeOff - sets with these values: 2
Pset_WallCommon - LoadBearing: no; ExtendToStructure: no

# IfcWallStandardCase: Basic Wall:Wall_Tiles_Refin-Prestigio-Calacatta-Oro-Soft-30x60 RC62, Basic Wall:Wall_Tiles_Refin-Prestigio-Calacatta-Oro-Soft-30x60 RC62:336183
In: Level 0
Type - PredefinedType: STANDARD; Material: <Unnamed> 1 mm, Prestigio-Calacatta-Oro-Soft-30x60 RC62 9 mm
Type - Pset_ElementShading - Color: WHITE
Type - Pset_FireRatingProperties - SurfaceSpreadOfFlame: INERT
Type - Pset_ManufacturerOccurrence - BarCode: N/A; SerialNumber: N/A
Type - Pset_ManufacturerTypeInformation - ArticleNumber: RC62; ModelReference: RC62; ModelLabel: CALACATTA ORO SOFT R 30X60; Manufacturer: info@refin.it; ProductionYear: N/A
Type - Pset_PrecastConcreteElementGeneral - SerialNumber: N/A
Type - Pset_ProductRequirements - Name: Prestigio_Calacatta_Oro_Soft_30X60 R; Category: Pr_35_93_96_19:Ceramic tiles
Type - Pset_QuantityTakeOff - Reference: N/A
Type - Pset_ReinforcementBarPitchOfWall - Description: PORCELAIN STONEWARE TILE; Reference: N/A
Type - Pset_WallCommon - Reference: N/A; IsExternal: no; AcousticRating: N/A; SurfaceSpreadOfFlame: INERT
Type - Pset_Warranty - WarrantyContent: N/A; Exclusions: N/A
Pset_QuantityTakeOff - sets with these values: 2
Pset_WallCommon - LoadBearing: no; ExtendToStructure: no

# IfcWallStandardCase: Basic Wall:Wall_Tiles_Refin-Prestigio-Calacatta-Oro-Soft-60x120 RC47, Basic Wall:Wall_Tiles_Refin-Prestigio-Calacatta-Oro-Soft-60x120 RC47:339723
In: Level 0
Type - PredefinedType: STANDARD; Material: <Unnamed> 1 mm, Prestigio-Calacatta-Oro-Soft-60x120 RC47 9 mm
Type - Pset_ElementShading - Color: WHITE
Type - Pset_FireRatingProperties - SurfaceSpreadOfFlame: INERT
Type - Pset_ManufacturerOccurrence - BarCode: N/A; SerialNumber: N/A
Type - Pset_ManufacturerTypeInformation - ArticleNumber: RC47; ModelReference: RC47; ModelLabel: CALACATTA ORO SOFT R 60X120; Manufacturer: info@refin.it; ProductionYear: N/A
Type - Pset_PrecastConcreteElementGeneral - SerialNumber: N/A
Type - Pset_ProductRequirements - Name: Prestigio_Calacatta_Oro_Soft_60X120 R; Category: Pr_35_93_96_19:Ceramic tiles
Type - Pset_QuantityTakeOff - Reference: N/A
Type - Pset_ReinforcementBarPitchOfWall - Description: PORCELAIN STONEWARE TILE; Reference: N/A
Type - Pset_WallCommon - Reference: N/A; IsExternal: no; AcousticRating: N/A; SurfaceSpreadOfFlame: INERT
Type - Pset_Warranty - WarrantyContent: N/A; Exclusions: N/A
Pset_QuantityTakeOff - sets with these values: 2
Pset_WallCommon - LoadBearing: no; ExtendToStructure: no

# IfcWallStandardCase: Basic Wall:Wall_Tiles_Refin-Prestigio-Calacatta-Oro-Soft-60x60 RB85, Basic Wall:Wall_Tiles_Refin-Prestigio-Calacatta-Oro-Soft-60x60 RB85:339715
In: Level 0
Type - PredefinedType: STANDARD; Material: <Unnamed> 1 mm, Prestigio-Calacatta-Oro-Soft-60x60 RB85 9 mm
Type - Pset_ElementShading - Color: WHITE
Type - Pset_FireRatingProperties - SurfaceSpreadOfFlame: INERT
Type - Pset_ManufacturerOccurrence - BarCode: N/A; SerialNumber: N/A
Type - Pset_ManufacturerTypeInformation - ArticleNumber: RB85; ModelReference: RB85; ModelLabel: CALACATTA ORO SOFT R 60X60; Manufacturer: info@refin.it; ProductionYear: N/A
Type - Pset_PrecastConcreteElementGeneral - SerialNumber: N/A
Type - Pset_ProductRequirements - Name: Prestigio_Calacatta_Oro_Soft_60X60 R; Category: Pr_35_93_96_19:Ceramic tiles
Type - Pset_QuantityTakeOff - Reference: N/A
Type - Pset_ReinforcementBarPitchOfWall - Description: PORCELAIN STONEWARE TILE; Reference: N/A
Type - Pset_WallCommon - Reference: N/A; IsExternal: no; AcousticRating: N/A; SurfaceSpreadOfFlame: INERT
Type - Pset_Warranty - WarrantyContent: N/A; Exclusions: N/A
Pset_QuantityTakeOff - sets with these values: 2
Pset_WallCommon - LoadBearing: no; ExtendToStructure: no
